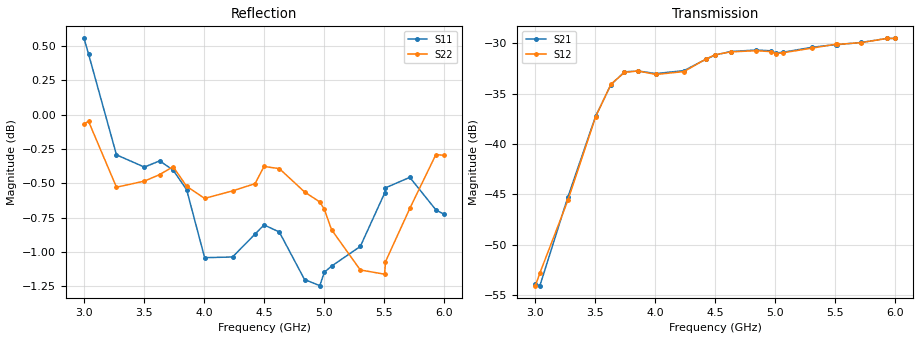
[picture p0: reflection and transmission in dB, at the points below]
!  26/11/2025  17:37:43
! Ref Plane: 0.000 mm
# MHZ S MA R  50
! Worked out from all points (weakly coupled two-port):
!   401 points, 3 GHz to 6 GHz, reference 50 ohm
!   highest |S21| = -29.50 dB at 5.933 GHz (marker M1); lowest = -54.1 dB at 3.038 GHz (marker M2)
!   lowest |S11| = -1.2 dB at 4.965 GHz (marker M3), VSWR 13.96, Z = 8.16 - j56.2 ohm
!   |S11| at or under -10 dB: nowhere
!   |S22| runs from -1.2 to 0.0 dB; largest |S21 - S12| = 0.0014
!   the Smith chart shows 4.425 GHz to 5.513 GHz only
!   S11 on the Smith chart (normalised r, x): 4.425 GHz: 0.10, +1.00; 4.628 GHz: 1.06, +4.42; 4.838 GHz: 0.50, -2.45; 5.062 GHz: 0.09, -0.68; 5.303 GHz: 0.06, -0.02; 5.513 GHz: 0.04, +0.57
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3000  1.066 -136.8  0.002019 45.2  0.001974 49.0  0.9923 -105.7
3037.5  1.052 -146.6  0.001976 36.2  0.002285 41.0  0.9943 -111.2
3270  0.9668 152.7  0.005431 -20.8  0.005237 -16.3  0.9409 -170.4
3502.5  0.9569 66.5  0.01378 -101.3  0.01369 -100.4  0.9457 112.9
3630  0.9619 11.4  0.01973 -157.9  0.01983 -156.4  0.9509 57.9
3742.5  0.9545 -38.2  0.02283 151.8  0.02269 153.3  0.9572 9.9
3855  0.9389 -83.6  0.02306 105.3  0.02307 106.7  0.9416 -36.1
4005  0.8869 -137.1  0.02239 52.5  0.02216 53.4  0.9321 -88.3
4237.5  0.8874 149.1  0.02315 -16.3  0.0229 -14.2  0.938 -160.9
4425  0.9046 89.7  0.02644 -73.3  0.02651 -71.8  0.9437 141.3
4500  0.9116 65.4  0.0277 -97.5  0.02779 -96.0  0.9574 118.4
4627.5  0.9062 24.2  0.02881 -138.2  0.0287 -137.1  0.9557 79.0
4837.5  0.8708 -43.0  0.02931 156.1  0.02908 157.7  0.9372 15.3
4965  0.8663 -82.6  0.02906 119.4  0.02878 120.7  0.9293 -20.9
5002.5  0.8761 -94.2  0.02833 108.8  0.02809 110.2  0.9237 -32.8
5062.5  0.8806 -111.1  0.02857 91.8  0.02839 93.0  0.908 -50.7
5302.5  0.8953 -177.3  0.03023 24.6  0.02995 25.9  0.8778 -119.6
5505  0.9362 121.7  0.03121 -32.7  0.03133 -30.8  0.8747 -174.6
5512.5  0.9404 120.3  0.03116 -34.4  0.03125 -32.4  0.8839 -177.5
5715  0.9487 62.6  0.03196 -92.6  0.03191 -90.4  0.9243 125.7
5932.5  0.9232 0.1  0.0335 -154.8  0.03348 -153.0  0.967 69.0
6000  0.9198 -19.8  0.03349 -173.9  0.03346 -172.5  0.9664 51.8
